VERSION 5.7 ;
  NOWIREEXTENSIONATPIN ON ;
  DIVIDERCHAR "/" ;
  BUSBITCHARS "[]" ;
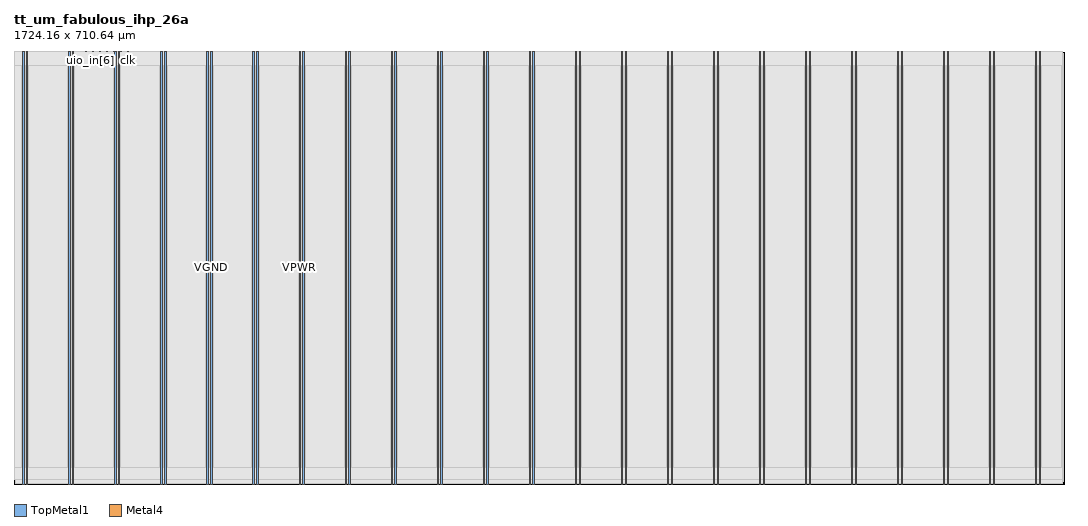
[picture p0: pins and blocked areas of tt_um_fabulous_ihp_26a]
MACRO tt_um_fabulous_ihp_26a
  CLASS BLOCK ;
  FOREIGN tt_um_fabulous_ihp_26a ;
  ORIGIN 0.000 0.000 ;
  SIZE 1724.160 BY 710.640 ;
  PIN VGND
    DIRECTION INOUT ;
    USE GROUND ;
    PORT
      LAYER TopMetal1 ;
        RECT 20.620 0.000 22.820 710.640 ;
    END
    PORT
      LAYER TopMetal1 ;
        RECT 96.220 0.000 98.420 710.640 ;
    END
    PORT
      LAYER TopMetal1 ;
        RECT 171.820 0.000 174.020 710.640 ;
    END
    PORT
      LAYER TopMetal1 ;
        RECT 247.420 0.000 249.620 710.640 ;
    END
    PORT
      LAYER TopMetal1 ;
        RECT 323.020 0.000 325.220 710.640 ;
    END
    PORT
      LAYER TopMetal1 ;
        RECT 398.620 0.000 400.820 710.640 ;
    END
    PORT
      LAYER TopMetal1 ;
        RECT 474.220 0.000 476.420 710.640 ;
    END
    PORT
      LAYER TopMetal1 ;
        RECT 549.820 0.000 552.020 710.640 ;
    END
    PORT
      LAYER TopMetal1 ;
        RECT 625.420 0.000 627.620 710.640 ;
    END
    PORT
      LAYER TopMetal1 ;
        RECT 701.020 0.000 703.220 710.640 ;
    END
    PORT
      LAYER TopMetal1 ;
        RECT 776.620 0.000 778.820 710.640 ;
    END
    PORT
      LAYER TopMetal1 ;
        RECT 852.220 0.000 854.420 710.640 ;
    END
    PORT
      LAYER TopMetal1 ;
        RECT 927.820 0.000 930.020 710.640 ;
    END
    PORT
      LAYER TopMetal1 ;
        RECT 1003.420 0.000 1005.620 710.640 ;
    END
    PORT
      LAYER TopMetal1 ;
        RECT 1079.020 0.000 1081.220 710.640 ;
    END
    PORT
      LAYER TopMetal1 ;
        RECT 1154.620 0.000 1156.820 710.640 ;
    END
    PORT
      LAYER TopMetal1 ;
        RECT 1230.220 0.000 1232.420 710.640 ;
    END
    PORT
      LAYER TopMetal1 ;
        RECT 1305.820 0.000 1308.020 710.640 ;
    END
    PORT
      LAYER TopMetal1 ;
        RECT 1381.420 0.000 1383.620 710.640 ;
    END
    PORT
      LAYER TopMetal1 ;
        RECT 1457.020 0.000 1459.220 710.640 ;
    END
    PORT
      LAYER TopMetal1 ;
        RECT 1532.620 0.000 1534.820 710.640 ;
    END
    PORT
      LAYER TopMetal1 ;
        RECT 1608.220 0.000 1610.420 710.640 ;
    END
    PORT
      LAYER TopMetal1 ;
        RECT 1683.820 0.000 1686.020 710.640 ;
    END
  END VGND
  PIN VPWR
    DIRECTION INOUT ;
    USE POWER ;
    PORT
      LAYER TopMetal1 ;
        RECT 14.420 0.000 16.620 710.640 ;
    END
    PORT
      LAYER TopMetal1 ;
        RECT 90.020 0.000 92.220 710.640 ;
    END
    PORT
      LAYER TopMetal1 ;
        RECT 165.620 0.000 167.820 710.640 ;
    END
    PORT
      LAYER TopMetal1 ;
        RECT 241.220 0.000 243.420 710.640 ;
    END
    PORT
      LAYER TopMetal1 ;
        RECT 316.820 0.000 319.020 710.640 ;
    END
    PORT
      LAYER TopMetal1 ;
        RECT 392.420 0.000 394.620 710.640 ;
    END
    PORT
      LAYER TopMetal1 ;
        RECT 468.020 0.000 470.220 710.640 ;
    END
    PORT
      LAYER TopMetal1 ;
        RECT 543.620 0.000 545.820 710.640 ;
    END
    PORT
      LAYER TopMetal1 ;
        RECT 619.220 0.000 621.420 710.640 ;
    END
    PORT
      LAYER TopMetal1 ;
        RECT 694.820 0.000 697.020 710.640 ;
    END
    PORT
      LAYER TopMetal1 ;
        RECT 770.420 0.000 772.620 710.640 ;
    END
    PORT
      LAYER TopMetal1 ;
        RECT 846.020 0.000 848.220 710.640 ;
    END
    PORT
      LAYER TopMetal1 ;
        RECT 921.620 0.000 923.820 710.640 ;
    END
    PORT
      LAYER TopMetal1 ;
        RECT 997.220 0.000 999.420 710.640 ;
    END
    PORT
      LAYER TopMetal1 ;
        RECT 1072.820 0.000 1075.020 710.640 ;
    END
    PORT
      LAYER TopMetal1 ;
        RECT 1148.420 0.000 1150.620 710.640 ;
    END
    PORT
      LAYER TopMetal1 ;
        RECT 1224.020 0.000 1226.220 710.640 ;
    END
    PORT
      LAYER TopMetal1 ;
        RECT 1299.620 0.000 1301.820 710.640 ;
    END
    PORT
      LAYER TopMetal1 ;
        RECT 1375.220 0.000 1377.420 710.640 ;
    END
    PORT
      LAYER TopMetal1 ;
        RECT 1450.820 0.000 1453.020 710.640 ;
    END
    PORT
      LAYER TopMetal1 ;
        RECT 1526.420 0.000 1528.620 710.640 ;
    END
    PORT
      LAYER TopMetal1 ;
        RECT 1602.020 0.000 1604.220 710.640 ;
    END
    PORT
      LAYER TopMetal1 ;
        RECT 1677.620 0.000 1679.820 710.640 ;
    END
  END VPWR
  PIN clk
    DIRECTION INPUT ;
    USE SIGNAL ;
    ANTENNAGATEAREA 2.901600 ;
    PORT
      LAYER Metal4 ;
        RECT 187.050 709.640 187.350 710.640 ;
    END
  END clk
  PIN ena
    DIRECTION INPUT ;
    USE SIGNAL ;
    PORT
      LAYER Metal4 ;
        RECT 190.890 709.640 191.190 710.640 ;
    END
  END ena
  PIN rst_n
    DIRECTION INPUT ;
    USE SIGNAL ;
    ANTENNAGATEAREA 0.180700 ;
    PORT
      LAYER Metal4 ;
        RECT 183.210 709.640 183.510 710.640 ;
    END
  END rst_n
  PIN ui_in[0]
    DIRECTION INPUT ;
    USE SIGNAL ;
    ANTENNAGATEAREA 0.180700 ;
    PORT
      LAYER Metal4 ;
        RECT 179.370 709.640 179.670 710.640 ;
    END
  END ui_in[0]
  PIN ui_in[1]
    DIRECTION INPUT ;
    USE SIGNAL ;
    ANTENNAGATEAREA 0.180700 ;
    PORT
      LAYER Metal4 ;
        RECT 175.530 709.640 175.830 710.640 ;
    END
  END ui_in[1]
  PIN ui_in[2]
    DIRECTION INPUT ;
    USE SIGNAL ;
    ANTENNAGATEAREA 0.335400 ;
    PORT
      LAYER Metal4 ;
        RECT 171.690 709.640 171.990 710.640 ;
    END
  END ui_in[2]
  PIN ui_in[3]
    DIRECTION INPUT ;
    USE SIGNAL ;
    ANTENNAGATEAREA 0.335400 ;
    PORT
      LAYER Metal4 ;
        RECT 167.850 709.640 168.150 710.640 ;
    END
  END ui_in[3]
  PIN ui_in[4]
    DIRECTION INPUT ;
    USE SIGNAL ;
    ANTENNAGATEAREA 0.335400 ;
    ANTENNADIFFAREA 4.030800 ;
    PORT
      LAYER Metal4 ;
        RECT 164.010 709.640 164.310 710.640 ;
    END
  END ui_in[4]
  PIN ui_in[5]
    DIRECTION INPUT ;
    USE SIGNAL ;
    ANTENNAGATEAREA 0.335400 ;
    ANTENNADIFFAREA 4.030800 ;
    PORT
      LAYER Metal4 ;
        RECT 160.170 709.640 160.470 710.640 ;
    END
  END ui_in[5]
  PIN ui_in[6]
    DIRECTION INPUT ;
    USE SIGNAL ;
    ANTENNAGATEAREA 0.335400 ;
    PORT
      LAYER Metal4 ;
        RECT 156.330 709.640 156.630 710.640 ;
    END
  END ui_in[6]
  PIN ui_in[7]
    DIRECTION INPUT ;
    USE SIGNAL ;
    ANTENNAGATEAREA 0.335400 ;
    ANTENNADIFFAREA 6.046200 ;
    PORT
      LAYER Metal4 ;
        RECT 152.490 709.640 152.790 710.640 ;
    END
  END ui_in[7]
  PIN uio_in[0]
    DIRECTION INPUT ;
    USE SIGNAL ;
    ANTENNAGATEAREA 0.335400 ;
    PORT
      LAYER Metal4 ;
        RECT 148.650 709.640 148.950 710.640 ;
    END
  END uio_in[0]
  PIN uio_in[1]
    DIRECTION INPUT ;
    USE SIGNAL ;
    ANTENNAGATEAREA 0.335400 ;
    PORT
      LAYER Metal4 ;
        RECT 144.810 709.640 145.110 710.640 ;
    END
  END uio_in[1]
  PIN uio_in[2]
    DIRECTION INPUT ;
    USE SIGNAL ;
    ANTENNAGATEAREA 0.289900 ;
    PORT
      LAYER Metal4 ;
        RECT 140.970 709.640 141.270 710.640 ;
    END
  END uio_in[2]
  PIN uio_in[3]
    DIRECTION INPUT ;
    USE SIGNAL ;
    ANTENNAGATEAREA 0.289900 ;
    PORT
      LAYER Metal4 ;
        RECT 137.130 709.640 137.430 710.640 ;
    END
  END uio_in[3]
  PIN uio_in[4]
    DIRECTION INPUT ;
    USE SIGNAL ;
    ANTENNAGATEAREA 0.335400 ;
    PORT
      LAYER Metal4 ;
        RECT 133.290 709.640 133.590 710.640 ;
    END
  END uio_in[4]
  PIN uio_in[5]
    DIRECTION INPUT ;
    USE SIGNAL ;
    ANTENNAGATEAREA 0.335400 ;
    ANTENNADIFFAREA 2.015400 ;
    PORT
      LAYER Metal4 ;
        RECT 129.450 709.640 129.750 710.640 ;
    END
  END uio_in[5]
  PIN uio_in[6]
    DIRECTION INPUT ;
    USE SIGNAL ;
    ANTENNAGATEAREA 0.289900 ;
    ANTENNADIFFAREA 2.015400 ;
    PORT
      LAYER Metal4 ;
        RECT 125.610 709.640 125.910 710.640 ;
    END
  END uio_in[6]
  PIN uio_in[7]
    DIRECTION INPUT ;
    USE SIGNAL ;
    ANTENNAGATEAREA 0.289900 ;
    ANTENNADIFFAREA 2.015400 ;
    PORT
      LAYER Metal4 ;
        RECT 121.770 709.640 122.070 710.640 ;
    END
  END uio_in[7]
  PIN uio_oe[0]
    DIRECTION OUTPUT ;
    USE SIGNAL ;
    ANTENNADIFFAREA 0.708600 ;
    PORT
      LAYER Metal4 ;
        RECT 56.490 709.640 56.790 710.640 ;
    END
  END uio_oe[0]
  PIN uio_oe[1]
    DIRECTION OUTPUT ;
    USE SIGNAL ;
    ANTENNADIFFAREA 0.708600 ;
    PORT
      LAYER Metal4 ;
        RECT 52.650 709.640 52.950 710.640 ;
    END
  END uio_oe[1]
  PIN uio_oe[2]
    DIRECTION OUTPUT ;
    USE SIGNAL ;
    ANTENNADIFFAREA 0.708600 ;
    PORT
      LAYER Metal4 ;
        RECT 48.810 709.640 49.110 710.640 ;
    END
  END uio_oe[2]
  PIN uio_oe[3]
    DIRECTION OUTPUT ;
    USE SIGNAL ;
    ANTENNADIFFAREA 0.708600 ;
    PORT
      LAYER Metal4 ;
        RECT 44.970 709.640 45.270 710.640 ;
    END
  END uio_oe[3]
  PIN uio_oe[4]
    DIRECTION OUTPUT ;
    USE SIGNAL ;
    ANTENNADIFFAREA 0.708600 ;
    PORT
      LAYER Metal4 ;
        RECT 41.130 709.640 41.430 710.640 ;
    END
  END uio_oe[4]
  PIN uio_oe[5]
    DIRECTION OUTPUT ;
    USE SIGNAL ;
    ANTENNADIFFAREA 0.708600 ;
    PORT
      LAYER Metal4 ;
        RECT 37.290 709.640 37.590 710.640 ;
    END
  END uio_oe[5]
  PIN uio_oe[6]
    DIRECTION OUTPUT ;
    USE SIGNAL ;
    ANTENNADIFFAREA 0.708600 ;
    PORT
      LAYER Metal4 ;
        RECT 33.450 709.640 33.750 710.640 ;
    END
  END uio_oe[6]
  PIN uio_oe[7]
    DIRECTION OUTPUT ;
    USE SIGNAL ;
    ANTENNADIFFAREA 0.708600 ;
    PORT
      LAYER Metal4 ;
        RECT 29.610 709.640 29.910 710.640 ;
    END
  END uio_oe[7]
  PIN uio_out[0]
    DIRECTION OUTPUT ;
    USE SIGNAL ;
    ANTENNADIFFAREA 0.708600 ;
    PORT
      LAYER Metal4 ;
        RECT 87.210 709.640 87.510 710.640 ;
    END
  END uio_out[0]
  PIN uio_out[1]
    DIRECTION OUTPUT ;
    USE SIGNAL ;
    ANTENNADIFFAREA 0.708600 ;
    PORT
      LAYER Metal4 ;
        RECT 83.370 709.640 83.670 710.640 ;
    END
  END uio_out[1]
  PIN uio_out[2]
    DIRECTION OUTPUT ;
    USE SIGNAL ;
    ANTENNADIFFAREA 0.708600 ;
    PORT
      LAYER Metal4 ;
        RECT 79.530 709.640 79.830 710.640 ;
    END
  END uio_out[2]
  PIN uio_out[3]
    DIRECTION OUTPUT ;
    USE SIGNAL ;
    ANTENNADIFFAREA 0.708600 ;
    PORT
      LAYER Metal4 ;
        RECT 75.690 709.640 75.990 710.640 ;
    END
  END uio_out[3]
  PIN uio_out[4]
    DIRECTION OUTPUT ;
    USE SIGNAL ;
    ANTENNADIFFAREA 0.708600 ;
    PORT
      LAYER Metal4 ;
        RECT 71.850 709.640 72.150 710.640 ;
    END
  END uio_out[4]
  PIN uio_out[5]
    DIRECTION OUTPUT ;
    USE SIGNAL ;
    ANTENNADIFFAREA 0.708600 ;
    PORT
      LAYER Metal4 ;
        RECT 68.010 709.640 68.310 710.640 ;
    END
  END uio_out[5]
  PIN uio_out[6]
    DIRECTION OUTPUT ;
    USE SIGNAL ;
    ANTENNADIFFAREA 0.708600 ;
    PORT
      LAYER Metal4 ;
        RECT 64.170 709.640 64.470 710.640 ;
    END
  END uio_out[6]
  PIN uio_out[7]
    DIRECTION OUTPUT ;
    USE SIGNAL ;
    ANTENNADIFFAREA 0.708600 ;
    PORT
      LAYER Metal4 ;
        RECT 60.330 709.640 60.630 710.640 ;
    END
  END uio_out[7]
  PIN uo_out[0]
    DIRECTION OUTPUT ;
    USE SIGNAL ;
    ANTENNADIFFAREA 0.708600 ;
    PORT
      LAYER Metal4 ;
        RECT 117.930 709.640 118.230 710.640 ;
    END
  END uo_out[0]
  PIN uo_out[1]
    DIRECTION OUTPUT ;
    USE SIGNAL ;
    ANTENNADIFFAREA 0.708600 ;
    PORT
      LAYER Metal4 ;
        RECT 114.090 709.640 114.390 710.640 ;
    END
  END uo_out[1]
  PIN uo_out[2]
    DIRECTION OUTPUT ;
    USE SIGNAL ;
    ANTENNADIFFAREA 0.708600 ;
    PORT
      LAYER Metal4 ;
        RECT 110.250 709.640 110.550 710.640 ;
    END
  END uo_out[2]
  PIN uo_out[3]
    DIRECTION OUTPUT ;
    USE SIGNAL ;
    ANTENNADIFFAREA 0.708600 ;
    PORT
      LAYER Metal4 ;
        RECT 106.410 709.640 106.710 710.640 ;
    END
  END uo_out[3]
  PIN uo_out[4]
    DIRECTION OUTPUT ;
    USE SIGNAL ;
    ANTENNADIFFAREA 0.708600 ;
    PORT
      LAYER Metal4 ;
        RECT 102.570 709.640 102.870 710.640 ;
    END
  END uo_out[4]
  PIN uo_out[5]
    DIRECTION OUTPUT ;
    USE SIGNAL ;
    ANTENNADIFFAREA 0.708600 ;
    PORT
      LAYER Metal4 ;
        RECT 98.730 709.640 99.030 710.640 ;
    END
  END uo_out[5]
  PIN uo_out[6]
    DIRECTION OUTPUT ;
    USE SIGNAL ;
    ANTENNADIFFAREA 0.708600 ;
    PORT
      LAYER Metal4 ;
        RECT 94.890 709.640 95.190 710.640 ;
    END
  END uo_out[6]
  PIN uo_out[7]
    DIRECTION OUTPUT ;
    USE SIGNAL ;
    ANTENNADIFFAREA 0.708600 ;
    PORT
      LAYER Metal4 ;
        RECT 91.050 709.640 91.350 710.640 ;
    END
  END uo_out[7]
  OBS
      LAYER GatPoly ;
        RECT 1.920 4.050 1723.680 707.010 ;
      LAYER Metal1 ;
        RECT 1.920 3.980 1723.680 707.080 ;
      LAYER Metal2 ;
        RECT 3.255 0.420 1721.865 710.365 ;
      LAYER Metal3 ;
        RECT 2.790 2.740 1721.905 710.325 ;
      LAYER Metal4 ;
        RECT 3.255 709.430 29.400 710.365 ;
        RECT 30.120 709.430 33.240 710.365 ;
        RECT 33.960 709.430 37.080 710.365 ;
        RECT 37.800 709.430 40.920 710.365 ;
        RECT 41.640 709.430 44.760 710.365 ;
        RECT 45.480 709.430 48.600 710.365 ;
        RECT 49.320 709.430 52.440 710.365 ;
        RECT 53.160 709.430 56.280 710.365 ;
        RECT 57.000 709.430 60.120 710.365 ;
        RECT 60.840 709.430 63.960 710.365 ;
        RECT 64.680 709.430 67.800 710.365 ;
        RECT 68.520 709.430 71.640 710.365 ;
        RECT 72.360 709.430 75.480 710.365 ;
        RECT 76.200 709.430 79.320 710.365 ;
        RECT 80.040 709.430 83.160 710.365 ;
        RECT 83.880 709.430 87.000 710.365 ;
        RECT 87.720 709.430 90.840 710.365 ;
        RECT 91.560 709.430 94.680 710.365 ;
        RECT 95.400 709.430 98.520 710.365 ;
        RECT 99.240 709.430 102.360 710.365 ;
        RECT 103.080 709.430 106.200 710.365 ;
        RECT 106.920 709.430 110.040 710.365 ;
        RECT 110.760 709.430 113.880 710.365 ;
        RECT 114.600 709.430 117.720 710.365 ;
        RECT 118.440 709.430 121.560 710.365 ;
        RECT 122.280 709.430 125.400 710.365 ;
        RECT 126.120 709.430 129.240 710.365 ;
        RECT 129.960 709.430 133.080 710.365 ;
        RECT 133.800 709.430 136.920 710.365 ;
        RECT 137.640 709.430 140.760 710.365 ;
        RECT 141.480 709.430 144.600 710.365 ;
        RECT 145.320 709.430 148.440 710.365 ;
        RECT 149.160 709.430 152.280 710.365 ;
        RECT 153.000 709.430 156.120 710.365 ;
        RECT 156.840 709.430 159.960 710.365 ;
        RECT 160.680 709.430 163.800 710.365 ;
        RECT 164.520 709.430 167.640 710.365 ;
        RECT 168.360 709.430 171.480 710.365 ;
        RECT 172.200 709.430 175.320 710.365 ;
        RECT 176.040 709.430 179.160 710.365 ;
        RECT 179.880 709.430 183.000 710.365 ;
        RECT 183.720 709.430 186.840 710.365 ;
        RECT 187.560 709.430 190.680 710.365 ;
        RECT 191.400 709.430 1721.865 710.365 ;
        RECT 3.255 0.420 1721.865 709.430 ;
      LAYER Metal5 ;
        RECT 1.330 7.250 1721.905 710.320 ;
      LAYER TopMetal1 ;
        RECT 0.820 26.900 12.780 687.100 ;
        RECT 18.260 26.900 18.980 687.100 ;
        RECT 24.460 26.900 88.380 687.100 ;
        RECT 93.860 26.900 94.580 687.100 ;
        RECT 100.060 26.900 163.980 687.100 ;
        RECT 169.460 26.900 170.180 687.100 ;
        RECT 175.660 26.900 239.580 687.100 ;
        RECT 245.060 26.900 245.780 687.100 ;
        RECT 251.260 26.900 315.180 687.100 ;
        RECT 320.660 26.900 321.380 687.100 ;
        RECT 326.860 26.900 390.780 687.100 ;
        RECT 396.260 26.900 396.980 687.100 ;
        RECT 402.460 26.900 466.380 687.100 ;
        RECT 471.860 26.900 472.580 687.100 ;
        RECT 478.060 26.900 541.980 687.100 ;
        RECT 547.460 26.900 548.180 687.100 ;
        RECT 553.660 26.900 617.580 687.100 ;
        RECT 623.060 26.900 623.780 687.100 ;
        RECT 629.260 26.900 693.180 687.100 ;
        RECT 698.660 26.900 699.380 687.100 ;
        RECT 704.860 26.900 768.780 687.100 ;
        RECT 774.260 26.900 774.980 687.100 ;
        RECT 780.460 26.900 844.380 687.100 ;
        RECT 849.860 26.900 850.580 687.100 ;
        RECT 856.060 26.900 919.980 687.100 ;
        RECT 925.460 26.900 926.180 687.100 ;
        RECT 931.660 26.900 995.580 687.100 ;
        RECT 1001.060 26.900 1001.780 687.100 ;
        RECT 1007.260 26.900 1071.180 687.100 ;
        RECT 1076.660 26.900 1077.380 687.100 ;
        RECT 1082.860 26.900 1146.780 687.100 ;
        RECT 1152.260 26.900 1152.980 687.100 ;
        RECT 1158.460 26.900 1222.380 687.100 ;
        RECT 1227.860 26.900 1228.580 687.100 ;
        RECT 1234.060 26.900 1297.980 687.100 ;
        RECT 1303.460 26.900 1304.180 687.100 ;
        RECT 1309.660 26.900 1373.580 687.100 ;
        RECT 1379.060 26.900 1379.780 687.100 ;
        RECT 1385.260 26.900 1449.180 687.100 ;
        RECT 1454.660 26.900 1455.380 687.100 ;
        RECT 1460.860 26.900 1524.780 687.100 ;
        RECT 1530.260 26.900 1530.980 687.100 ;
        RECT 1536.460 26.900 1600.380 687.100 ;
        RECT 1605.860 26.900 1606.580 687.100 ;
        RECT 1612.060 26.900 1675.980 687.100 ;
        RECT 1681.460 26.900 1682.180 687.100 ;
        RECT 1687.660 26.900 1719.300 687.100 ;
  END
END tt_um_fabulous_ihp_26a
END LIBRARY

